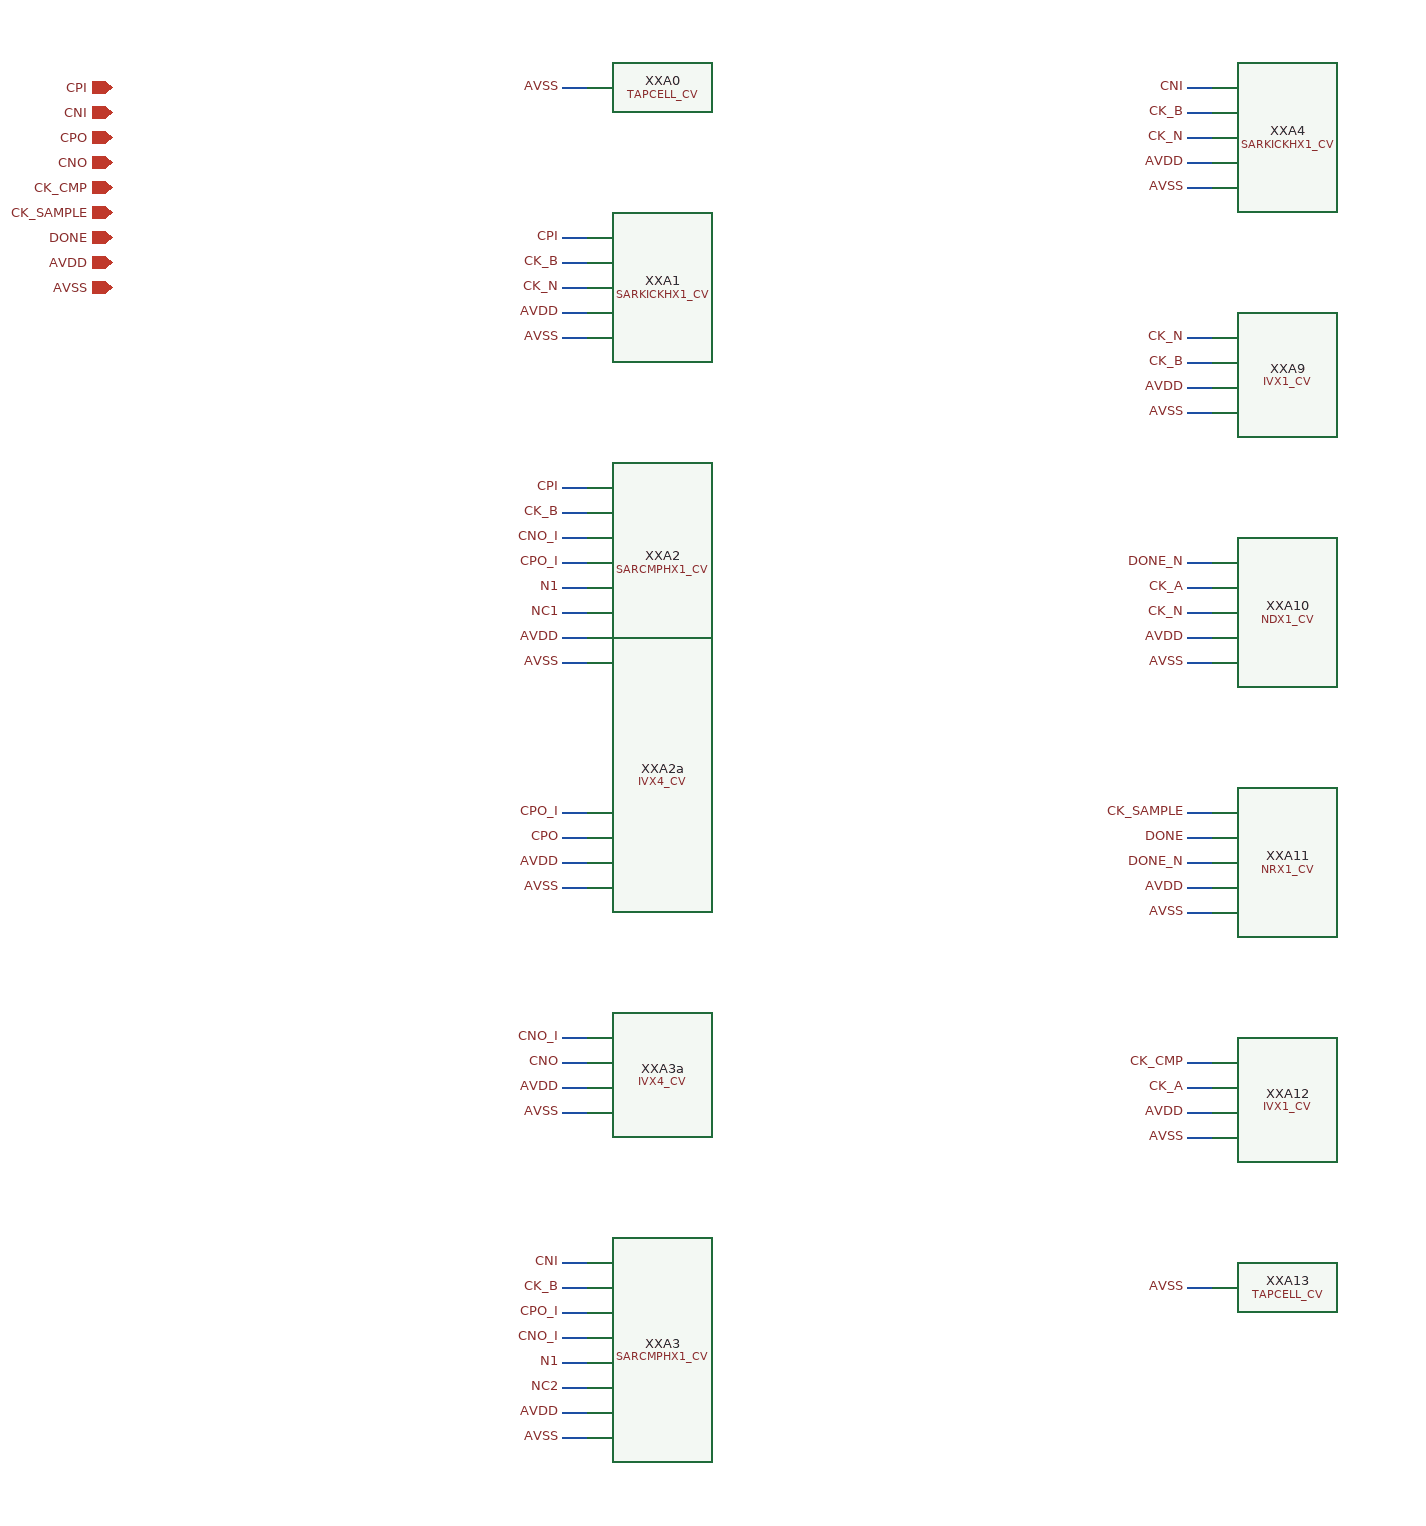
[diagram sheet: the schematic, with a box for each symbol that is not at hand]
v {xschem version=3.0.0 file_version=1.2 }
G {}
K {}
V {}
S {}
E {}
C {devices/iopin.sym} 0 0 0 0 {name=p0 lab=CPI}
C {devices/iopin.sym} 0 20 0 0 {name=p1 lab=CNI}
C {devices/iopin.sym} 0 40 0 0 {name=p2 lab=CPO}
C {devices/iopin.sym} 0 60 0 0 {name=p3 lab=CNO}
C {devices/iopin.sym} 0 80 0 0 {name=p4 lab=CK_CMP}
C {devices/iopin.sym} 0 100 0 0 {name=p5 lab=CK_SAMPLE}
C {devices/iopin.sym} 0 120 0 0 {name=p6 lab=DONE}
C {devices/iopin.sym} 0 140 0 0 {name=p7 lab=AVDD}
C {devices/iopin.sym} 0 160 0 0 {name=p8 lab=AVSS}
C {SAR9B/TAPCELL_CV.sym} 400 0 0 0 {name=XXA0}
N 360.0 0.0 380.0 0.0 {lab=AVSS}
C {devices/lab_pin.sym} 360.0 0.0 0 0 {name=l0 sig_type=std_logic lab=AVSS }
C {SAR9B/SARKICKHX1_CV.sym} 400 120.0 0 0 {name=XXA1}
N 360.0 120.0 380.0 120.0 {lab=CPI}
C {devices/lab_pin.sym} 360.0 120.0 0 0 {name=l1 sig_type=std_logic lab=CPI }
N 360.0 140.0 380.0 140.0 {lab=CK_B}
C {devices/lab_pin.sym} 360.0 140.0 0 0 {name=l2 sig_type=std_logic lab=CK_B }
N 360.0 160.0 380.0 160.0 {lab=CK_N}
C {devices/lab_pin.sym} 360.0 160.0 0 0 {name=l3 sig_type=std_logic lab=CK_N }
N 360.0 180.0 380.0 180.0 {lab=AVDD}
C {devices/lab_pin.sym} 360.0 180.0 0 0 {name=l4 sig_type=std_logic lab=AVDD }
N 360.0 200.0 380.0 200.0 {lab=AVSS}
C {devices/lab_pin.sym} 360.0 200.0 0 0 {name=l5 sig_type=std_logic lab=AVSS }
C {SAR9B/SARCMPHX1_CV.sym} 400 320.0 0 0 {name=XXA2}
N 360.0 320.0 380.0 320.0 {lab=CPI}
C {devices/lab_pin.sym} 360.0 320.0 0 0 {name=l6 sig_type=std_logic lab=CPI }
N 360.0 340.0 380.0 340.0 {lab=CK_B}
C {devices/lab_pin.sym} 360.0 340.0 0 0 {name=l7 sig_type=std_logic lab=CK_B }
N 360.0 360.0 380.0 360.0 {lab=CNO_I}
C {devices/lab_pin.sym} 360.0 360.0 0 0 {name=l8 sig_type=std_logic lab=CNO_I }
N 360.0 380.0 380.0 380.0 {lab=CPO_I}
C {devices/lab_pin.sym} 360.0 380.0 0 0 {name=l9 sig_type=std_logic lab=CPO_I }
N 360.0 400.0 380.0 400.0 {lab=N1}
C {devices/lab_pin.sym} 360.0 400.0 0 0 {name=l10 sig_type=std_logic lab=N1 }
N 360.0 420.0 380.0 420.0 {lab=NC1}
C {devices/lab_pin.sym} 360.0 420.0 0 0 {name=l11 sig_type=std_logic lab=NC1 }
N 360.0 440.0 380.0 440.0 {lab=AVDD}
C {devices/lab_pin.sym} 360.0 440.0 0 0 {name=l12 sig_type=std_logic lab=AVDD }
N 360.0 460.0 380.0 460.0 {lab=AVSS}
C {devices/lab_pin.sym} 360.0 460.0 0 0 {name=l13 sig_type=std_logic lab=AVSS }
C {SAR9B/IVX4_CV.sym} 400 580.0 0 0 {name=XXA2a}
N 360.0 580.0 380.0 580.0 {lab=CPO_I}
C {devices/lab_pin.sym} 360.0 580.0 0 0 {name=l14 sig_type=std_logic lab=CPO_I }
N 360.0 600.0 380.0 600.0 {lab=CPO}
C {devices/lab_pin.sym} 360.0 600.0 0 0 {name=l15 sig_type=std_logic lab=CPO }
N 360.0 620.0 380.0 620.0 {lab=AVDD}
C {devices/lab_pin.sym} 360.0 620.0 0 0 {name=l16 sig_type=std_logic lab=AVDD }
N 360.0 640.0 380.0 640.0 {lab=AVSS}
C {devices/lab_pin.sym} 360.0 640.0 0 0 {name=l17 sig_type=std_logic lab=AVSS }
C {SAR9B/IVX4_CV.sym} 400 760.0 0 0 {name=XXA3a}
N 360.0 760.0 380.0 760.0 {lab=CNO_I}
C {devices/lab_pin.sym} 360.0 760.0 0 0 {name=l18 sig_type=std_logic lab=CNO_I }
N 360.0 780.0 380.0 780.0 {lab=CNO}
C {devices/lab_pin.sym} 360.0 780.0 0 0 {name=l19 sig_type=std_logic lab=CNO }
N 360.0 800.0 380.0 800.0 {lab=AVDD}
C {devices/lab_pin.sym} 360.0 800.0 0 0 {name=l20 sig_type=std_logic lab=AVDD }
N 360.0 820.0 380.0 820.0 {lab=AVSS}
C {devices/lab_pin.sym} 360.0 820.0 0 0 {name=l21 sig_type=std_logic lab=AVSS }
C {SAR9B/SARCMPHX1_CV.sym} 400 940.0 0 0 {name=XXA3}
N 360.0 940.0 380.0 940.0 {lab=CNI}
C {devices/lab_pin.sym} 360.0 940.0 0 0 {name=l22 sig_type=std_logic lab=CNI }
N 360.0 960.0 380.0 960.0 {lab=CK_B}
C {devices/lab_pin.sym} 360.0 960.0 0 0 {name=l23 sig_type=std_logic lab=CK_B }
N 360.0 980.0 380.0 980.0 {lab=CPO_I}
C {devices/lab_pin.sym} 360.0 980.0 0 0 {name=l24 sig_type=std_logic lab=CPO_I }
N 360.0 1000.0 380.0 1000.0 {lab=CNO_I}
C {devices/lab_pin.sym} 360.0 1000.0 0 0 {name=l25 sig_type=std_logic lab=CNO_I }
N 360.0 1020.0 380.0 1020.0 {lab=N1}
C {devices/lab_pin.sym} 360.0 1020.0 0 0 {name=l26 sig_type=std_logic lab=N1 }
N 360.0 1040.0 380.0 1040.0 {lab=NC2}
C {devices/lab_pin.sym} 360.0 1040.0 0 0 {name=l27 sig_type=std_logic lab=NC2 }
N 360.0 1060.0 380.0 1060.0 {lab=AVDD}
C {devices/lab_pin.sym} 360.0 1060.0 0 0 {name=l28 sig_type=std_logic lab=AVDD }
N 360.0 1080.0 380.0 1080.0 {lab=AVSS}
C {devices/lab_pin.sym} 360.0 1080.0 0 0 {name=l29 sig_type=std_logic lab=AVSS }
C {SAR9B/SARKICKHX1_CV.sym} 900 0 0 0 {name=XXA4}
N 860.0 0.0 880.0 0.0 {lab=CNI}
C {devices/lab_pin.sym} 860.0 0.0 0 0 {name=l30 sig_type=std_logic lab=CNI }
N 860.0 20.0 880.0 20.0 {lab=CK_B}
C {devices/lab_pin.sym} 860.0 20.0 0 0 {name=l31 sig_type=std_logic lab=CK_B }
N 860.0 40.0 880.0 40.0 {lab=CK_N}
C {devices/lab_pin.sym} 860.0 40.0 0 0 {name=l32 sig_type=std_logic lab=CK_N }
N 860.0 60.0 880.0 60.0 {lab=AVDD}
C {devices/lab_pin.sym} 860.0 60.0 0 0 {name=l33 sig_type=std_logic lab=AVDD }
N 860.0 80.0 880.0 80.0 {lab=AVSS}
C {devices/lab_pin.sym} 860.0 80.0 0 0 {name=l34 sig_type=std_logic lab=AVSS }
C {SAR9B/IVX1_CV.sym} 900 200.0 0 0 {name=XXA9}
N 860.0 200.0 880.0 200.0 {lab=CK_N}
C {devices/lab_pin.sym} 860.0 200.0 0 0 {name=l35 sig_type=std_logic lab=CK_N }
N 860.0 220.0 880.0 220.0 {lab=CK_B}
C {devices/lab_pin.sym} 860.0 220.0 0 0 {name=l36 sig_type=std_logic lab=CK_B }
N 860.0 240.0 880.0 240.0 {lab=AVDD}
C {devices/lab_pin.sym} 860.0 240.0 0 0 {name=l37 sig_type=std_logic lab=AVDD }
N 860.0 260.0 880.0 260.0 {lab=AVSS}
C {devices/lab_pin.sym} 860.0 260.0 0 0 {name=l38 sig_type=std_logic lab=AVSS }
C {SAR9B/NDX1_CV.sym} 900 380.0 0 0 {name=XXA10}
N 860.0 380.0 880.0 380.0 {lab=DONE_N}
C {devices/lab_pin.sym} 860.0 380.0 0 0 {name=l39 sig_type=std_logic lab=DONE_N }
N 860.0 400.0 880.0 400.0 {lab=CK_A}
C {devices/lab_pin.sym} 860.0 400.0 0 0 {name=l40 sig_type=std_logic lab=CK_A }
N 860.0 420.0 880.0 420.0 {lab=CK_N}
C {devices/lab_pin.sym} 860.0 420.0 0 0 {name=l41 sig_type=std_logic lab=CK_N }
N 860.0 440.0 880.0 440.0 {lab=AVDD}
C {devices/lab_pin.sym} 860.0 440.0 0 0 {name=l42 sig_type=std_logic lab=AVDD }
N 860.0 460.0 880.0 460.0 {lab=AVSS}
C {devices/lab_pin.sym} 860.0 460.0 0 0 {name=l43 sig_type=std_logic lab=AVSS }
C {SAR9B/NRX1_CV.sym} 900 580.0 0 0 {name=XXA11}
N 860.0 580.0 880.0 580.0 {lab=CK_SAMPLE}
C {devices/lab_pin.sym} 860.0 580.0 0 0 {name=l44 sig_type=std_logic lab=CK_SAMPLE }
N 860.0 600.0 880.0 600.0 {lab=DONE}
C {devices/lab_pin.sym} 860.0 600.0 0 0 {name=l45 sig_type=std_logic lab=DONE }
N 860.0 620.0 880.0 620.0 {lab=DONE_N}
C {devices/lab_pin.sym} 860.0 620.0 0 0 {name=l46 sig_type=std_logic lab=DONE_N }
N 860.0 640.0 880.0 640.0 {lab=AVDD}
C {devices/lab_pin.sym} 860.0 640.0 0 0 {name=l47 sig_type=std_logic lab=AVDD }
N 860.0 660.0 880.0 660.0 {lab=AVSS}
C {devices/lab_pin.sym} 860.0 660.0 0 0 {name=l48 sig_type=std_logic lab=AVSS }
C {SAR9B/IVX1_CV.sym} 900 780.0 0 0 {name=XXA12}
N 860.0 780.0 880.0 780.0 {lab=CK_CMP}
C {devices/lab_pin.sym} 860.0 780.0 0 0 {name=l49 sig_type=std_logic lab=CK_CMP }
N 860.0 800.0 880.0 800.0 {lab=CK_A}
C {devices/lab_pin.sym} 860.0 800.0 0 0 {name=l50 sig_type=std_logic lab=CK_A }
N 860.0 820.0 880.0 820.0 {lab=AVDD}
C {devices/lab_pin.sym} 860.0 820.0 0 0 {name=l51 sig_type=std_logic lab=AVDD }
N 860.0 840.0 880.0 840.0 {lab=AVSS}
C {devices/lab_pin.sym} 860.0 840.0 0 0 {name=l52 sig_type=std_logic lab=AVSS }
C {SAR9B/TAPCELL_CV.sym} 900 960.0 0 0 {name=XXA13}
N 860.0 960.0 880.0 960.0 {lab=AVSS}
C {devices/lab_pin.sym} 860.0 960.0 0 0 {name=l53 sig_type=std_logic lab=AVSS }
